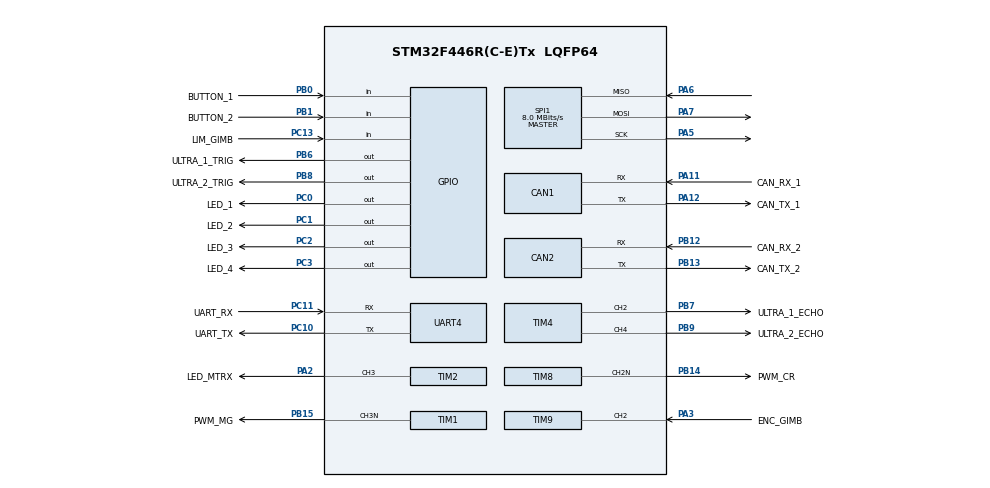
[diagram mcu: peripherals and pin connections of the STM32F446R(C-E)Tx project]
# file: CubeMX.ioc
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CAN1.CalculateTimeQuantum=1000.0
CAN2.CalculateTimeQuantum=1000.0
Mcu.Family=STM32F4
Mcu.Name=STM32F446R(C-E)Tx
Mcu.Package=LQFP64
NVIC.PriorityGroup=NVIC_PRIORITYGROUP_4
PA11.GPIO_Label=CAN_RX_1
PA11.Mode=Master
PA11.Signal=CAN1_RX
PA12.GPIO_Label=CAN_TX_1
PA12.Mode=Master
PA12.Signal=CAN1_TX
PA13.GPIO_Label=SWD_IO
PA13.Mode=Serial_Wire
PA13.Signal=SYS_JTMS-SWDIO
PA14.GPIO_Label=SWD_CLK
PA14.Mode=Serial_Wire
PA14.Signal=SYS_JTCK-SWCLK
PA2.GPIO_Label=LED_MTRX
PA2.Signal=S_TIM2_CH3
PA3.GPIO_Label=ENC_GIMB
PA3.Signal=S_TIM9_CH2
PA5.Mode=Full_Duplex_Master
PA5.Signal=SPI1_SCK
PA6.Mode=Full_Duplex_Master
PA6.Signal=SPI1_MISO
PA7.Mode=Full_Duplex_Master
PA7.Signal=SPI1_MOSI
PB0.GPIO_Label=BUTTON_1
PB0.Signal=GPIO_Input
PB1.GPIO_Label=BUTTON_2
PB1.Signal=GPIO_Input
PB12.GPIO_Label=CAN_RX_2
PB12.Mode=Slave
PB12.Signal=CAN2_RX
PB13.GPIO_Label=CAN_TX_2
PB13.Mode=Slave
PB13.Signal=CAN2_TX
PB14.GPIO_Label=PWM_CR
PB14.Mode=PWM Generation2 CH2N
PB14.Signal=TIM8_CH2N
PB15.GPIO_Label=PWM_MG
PB15.Mode=PWM Generation3 CH3N
PB15.Signal=TIM1_CH3N
PB6.GPIO_Label=ULTRA_1_TRIG
PB6.Signal=GPIO_Output
PB7.GPIO_Label=ULTRA_1_ECHO
PB7.Signal=S_TIM4_CH2
PB8.GPIO_Label=ULTRA_2_TRIG
PB8.Signal=GPIO_Output
PB9.GPIO_Label=ULTRA_2_ECHO
PB9.Signal=S_TIM4_CH4
PC0.GPIO_Label=LED_1
PC0.Signal=GPIO_Output
PC1.GPIO_Label=LED_2
PC1.Signal=GPIO_Output
PC10.GPIO_Label=UART_TX
PC10.Mode=Asynchronous
PC10.Signal=UART4_TX
PC11.GPIO_Label=UART_RX
PC11.Mode=Asynchronous
PC11.Signal=UART4_RX
PC13.GPIO_Label=LIM_GIMB
PC13.Signal=GPIO_Input
PC2.GPIO_Label=LED_3
PC2.Signal=GPIO_Output
PC3.GPIO_Label=LED_4
PC3.Signal=GPIO_Output
PH0-OSC_IN.Mode=HSE-External-Oscillator
PH0-OSC_IN.Signal=RCC_OSC_IN
PH1-OSC_OUT.Mode=HSE-External-Oscillator
PH1-OSC_OUT.Signal=RCC_OSC_OUT
ProjectManager.HeapSize=0x200
ProjectManager.StackSize=0x400
ProjectManager.TargetToolchain=EWARM V8.32
RCC.CortexFreq_Value=16000000
RCC.USBFreq_Value=96000000
RCC.VCOOutputFreq_Value=192000000
SH.S_TIM2_CH3.0=TIM2_CH3,PWM Generation3 CH3
SH.S_TIM4_CH2.0=TIM4_CH2,PWM Generation2 CH2
SH.S_TIM4_CH4.0=TIM4_CH4,PWM Generation4 CH4
SH.S_TIM9_CH2.0=TIM9_CH2,PWM_Input_2
SPI1.CalculateBaudRate=8.0 MBits/s
SPI1.Direction=SPI_DIRECTION_2LINES
SPI1.Mode=SPI_MODE_MASTER
SPI1.VirtualType=VM_MASTER
TIM1.Channel-PWM\ Generation3\ CH3N=TIM_CHANNEL_3
TIM2.Channel-PWM\ Generation3\ CH3=TIM_CHANNEL_3
TIM4.Channel-PWM\ Generation2\ CH2=TIM_CHANNEL_2
TIM4.Channel-PWM\ Generation4\ CH4=TIM_CHANNEL_4
TIM8.Channel-PWM\ Generation2\ CH2N=TIM_CHANNEL_2
UART4.VirtualMode=Asynchronous
VP_TIM12_VS_OPM.Mode=OPM_bit
VP_TIM6_VS_ClockSourceINT.Mode=Enable_Timer
VP_TIM7_VS_ClockSourceINT.Mode=Enable_Timer
board=custom

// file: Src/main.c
/* USER CODE BEGIN Header */
/**
  ******************************************************************************
  * @file           : main.c
  * @brief          : Main program body
  ******************************************************************************
  * @attention
  *
  * <h2><center>&copy; Copyright (c) 2020 STMicroelectronics.
  * All rights reserved.</center></h2>
  *
  * This software component is licensed by ST under BSD 3-Clause license,
  * the "License"; You may not use this file except in compliance with the
  * License. You may obtain a copy of the License at:
  *                        opensource.org/licenses/BSD-3-Clause
  *
  ******************************************************************************
  */
/* USER CODE END Header */

#include "main.h"

CAN_HandleTypeDef hcan1;
CAN_HandleTypeDef hcan2;

SPI_HandleTypeDef hspi1;

TIM_HandleTypeDef htim1;
TIM_HandleTypeDef htim2;
TIM_HandleTypeDef htim4;
TIM_HandleTypeDef htim6;
TIM_HandleTypeDef htim7;
TIM_HandleTypeDef htim8;
TIM_HandleTypeDef htim9;
TIM_HandleTypeDef htim12;

UART_HandleTypeDef huart4;

void SystemClock_Config(void);
static void MX_GPIO_Init(void);
static void MX_CAN1_Init(void);
static void MX_CAN2_Init(void);
static void MX_SPI1_Init(void);
static void MX_TIM1_Init(void);
static void MX_TIM2_Init(void);
static void MX_TIM4_Init(void);
static void MX_TIM6_Init(void);
static void MX_TIM7_Init(void);
static void MX_TIM8_Init(void);
static void MX_TIM9_Init(void);
static void MX_TIM12_Init(void);
static void MX_UART4_Init(void);

int main(void)
{

  /* MCU Configuration--------------------------------------------------------*/

  /* Reset of all peripherals, Initializes the Flash interface and the Systick. */
  HAL_Init();

  /* Configure the system clock */
  SystemClock_Config();

  /* Initialize all configured peripherals */
  MX_GPIO_Init();
  MX_CAN1_Init();
  MX_CAN2_Init();
  MX_SPI1_Init();
  MX_TIM1_Init();
  MX_TIM2_Init();
  MX_TIM4_Init();
  MX_TIM6_Init();
  MX_TIM7_Init();
  MX_TIM8_Init();
  MX_TIM9_Init();
  MX_TIM12_Init();
  MX_UART4_Init();

  /* Infinite loop */
  while (1)
  {

  }
}

void SystemClock_Config(void)
{
  RCC_OscInitTypeDef RCC_OscInitStruct = {0};
  RCC_ClkInitTypeDef RCC_ClkInitStruct = {0};

  /** Configure the main internal regulator output voltage
  */
  __HAL_RCC_PWR_CLK_ENABLE();
  __HAL_PWR_VOLTAGESCALING_CONFIG(PWR_REGULATOR_VOLTAGE_SCALE1);
  /** Initializes the CPU, AHB and APB busses clocks
  */
  RCC_OscInitStruct.OscillatorType = RCC_OSCILLATORTYPE_HSE;
  RCC_OscInitStruct.HSEState = RCC_HSE_ON;
  RCC_OscInitStruct.PLL.PLLState = RCC_PLL_ON;
  RCC_OscInitStruct.PLL.PLLSource = RCC_PLLSOURCE_HSE;
  RCC_OscInitStruct.PLL.PLLM = 25;
  RCC_OscInitStruct.PLL.PLLN = 360;
  RCC_OscInitStruct.PLL.PLLP = RCC_PLLP_DIV2;
  RCC_OscInitStruct.PLL.PLLQ = 2;
  RCC_OscInitStruct.PLL.PLLR = 2;
  if (HAL_RCC_OscConfig(&RCC_OscInitStruct) != HAL_OK)
  {
    Error_Handler();
  }
  /** Activate the Over-Drive mode
  */
  if (HAL_PWREx_EnableOverDrive() != HAL_OK)
  {
    Error_Handler();
  }
  /** Initializes the CPU, AHB and APB busses clocks
  */
  RCC_ClkInitStruct.ClockType = RCC_CLOCKTYPE_HCLK|RCC_CLOCKTYPE_SYSCLK
                              |RCC_CLOCKTYPE_PCLK1|RCC_CLOCKTYPE_PCLK2;
  RCC_ClkInitStruct.SYSCLKSource = RCC_SYSCLKSOURCE_PLLCLK;
  RCC_ClkInitStruct.AHBCLKDivider = RCC_SYSCLK_DIV1;
  RCC_ClkInitStruct.APB1CLKDivider = RCC_HCLK_DIV4;
  RCC_ClkInitStruct.APB2CLKDivider = RCC_HCLK_DIV2;

  if (HAL_RCC_ClockConfig(&RCC_ClkInitStruct, FLASH_LATENCY_5) != HAL_OK)
  {
    Error_Handler();
  }
}

static void MX_CAN1_Init(void)
{

  hcan1.Instance = CAN1;
  hcan1.Init.Prescaler = 16;
  hcan1.Init.Mode = CAN_MODE_NORMAL;
  hcan1.Init.SyncJumpWidth = CAN_SJW_1TQ;
  hcan1.Init.TimeSeg1 = CAN_BS1_1TQ;
  hcan1.Init.TimeSeg2 = CAN_BS2_1TQ;
  hcan1.Init.TimeTriggeredMode = DISABLE;
  hcan1.Init.AutoBusOff = DISABLE;
  hcan1.Init.AutoWakeUp = DISABLE;
  hcan1.Init.AutoRetransmission = DISABLE;
  hcan1.Init.ReceiveFifoLocked = DISABLE;
  hcan1.Init.TransmitFifoPriority = DISABLE;
  if (HAL_CAN_Init(&hcan1) != HAL_OK)
  {
    Error_Handler();
  }

}

static void MX_CAN2_Init(void)
{

  hcan2.Instance = CAN2;
  hcan2.Init.Prescaler = 16;
  hcan2.Init.Mode = CAN_MODE_NORMAL;
  hcan2.Init.SyncJumpWidth = CAN_SJW_1TQ;
  hcan2.Init.TimeSeg1 = CAN_BS1_1TQ;
  hcan2.Init.TimeSeg2 = CAN_BS2_1TQ;
  hcan2.Init.TimeTriggeredMode = DISABLE;
  hcan2.Init.AutoBusOff = DISABLE;
  hcan2.Init.AutoWakeUp = DISABLE;
  hcan2.Init.AutoRetransmission = DISABLE;
  hcan2.Init.ReceiveFifoLocked = DISABLE;
  hcan2.Init.TransmitFifoPriority = DISABLE;
  if (HAL_CAN_Init(&hcan2) != HAL_OK)
  {
    Error_Handler();
  }

}

static void MX_SPI1_Init(void)
{

  /* SPI1 parameter configuration*/
  hspi1.Instance = SPI1;
  hspi1.Init.Mode = SPI_MODE_MASTER;
  hspi1.Init.Direction = SPI_DIRECTION_2LINES;
  hspi1.Init.DataSize = SPI_DATASIZE_8BIT;
  hspi1.Init.CLKPolarity = SPI_POLARITY_LOW;
  hspi1.Init.CLKPhase = SPI_PHASE_1EDGE;
  hspi1.Init.NSS = SPI_NSS_SOFT;
  hspi1.Init.BaudRatePrescaler = SPI_BAUDRATEPRESCALER_2;
  hspi1.Init.FirstBit = SPI_FIRSTBIT_MSB;
  hspi1.Init.TIMode = SPI_TIMODE_DISABLE;
  hspi1.Init.CRCCalculation = SPI_CRCCALCULATION_DISABLE;
  hspi1.Init.CRCPolynomial = 10;
  if (HAL_SPI_Init(&hspi1) != HAL_OK)
  {
    Error_Handler();
  }

}

static void MX_TIM1_Init(void)
{

  TIM_MasterConfigTypeDef sMasterConfig = {0};
  TIM_OC_InitTypeDef sConfigOC = {0};
  TIM_BreakDeadTimeConfigTypeDef sBreakDeadTimeConfig = {0};

  htim1.Instance = TIM1;
  htim1.Init.Prescaler = 0;
  htim1.Init.CounterMode = TIM_COUNTERMODE_UP;
  htim1.Init.Period = 0;
  htim1.Init.ClockDivision = TIM_CLOCKDIVISION_DIV1;
  htim1.Init.RepetitionCounter = 0;
  htim1.Init.AutoReloadPreload = TIM_AUTORELOAD_PRELOAD_DISABLE;
  if (HAL_TIM_PWM_Init(&htim1) != HAL_OK)
  {
    Error_Handler();
  }
  sMasterConfig.MasterOutputTrigger = TIM_TRGO_RESET;
  sMasterConfig.MasterSlaveMode = TIM_MASTERSLAVEMODE_DISABLE;
  if (HAL_TIMEx_MasterConfigSynchronization(&htim1, &sMasterConfig) != HAL_OK)
  {
    Error_Handler();
  }
  sConfigOC.OCMode = TIM_OCMODE_PWM1;
  sConfigOC.Pulse = 0;
  sConfigOC.OCPolarity = TIM_OCPOLARITY_HIGH;
  sConfigOC.OCNPolarity = TIM_OCNPOLARITY_HIGH;
  sConfigOC.OCFastMode = TIM_OCFAST_DISABLE;
  sConfigOC.OCIdleState = TIM_OCIDLESTATE_RESET;
  sConfigOC.OCNIdleState = TIM_OCNIDLESTATE_RESET;
  if (HAL_TIM_PWM_ConfigChannel(&htim1, &sConfigOC, TIM_CHANNEL_3) != HAL_OK)
  {
    Error_Handler();
  }
  sBreakDeadTimeConfig.OffStateRunMode = TIM_OSSR_DISABLE;
  sBreakDeadTimeConfig.OffStateIDLEMode = TIM_OSSI_DISABLE;
  sBreakDeadTimeConfig.LockLevel = TIM_LOCKLEVEL_OFF;
  sBreakDeadTimeConfig.DeadTime = 0;
  sBreakDeadTimeConfig.BreakState = TIM_BREAK_DISABLE;
  sBreakDeadTimeConfig.BreakPolarity = TIM_BREAKPOLARITY_HIGH;
  sBreakDeadTimeConfig.AutomaticOutput = TIM_AUTOMATICOUTPUT_DISABLE;
  if (HAL_TIMEx_ConfigBreakDeadTime(&htim1, &sBreakDeadTimeConfig) != HAL_OK)
  {
    Error_Handler();
  }
  HAL_TIM_MspPostInit(&htim1);

}

static void MX_TIM2_Init(void)
{

  TIM_MasterConfigTypeDef sMasterConfig = {0};
  TIM_OC_InitTypeDef sConfigOC = {0};

  htim2.Instance = TIM2;
  htim2.Init.Prescaler = 0;
  htim2.Init.CounterMode = TIM_COUNTERMODE_UP;
  htim2.Init.Period = 0;
  htim2.Init.ClockDivision = TIM_CLOCKDIVISION_DIV1;
  htim2.Init.AutoReloadPreload = TIM_AUTORELOAD_PRELOAD_DISABLE;
  if (HAL_TIM_PWM_Init(&htim2) != HAL_OK)
  {
    Error_Handler();
  }
  sMasterConfig.MasterOutputTrigger = TIM_TRGO_RESET;
  sMasterConfig.MasterSlaveMode = TIM_MASTERSLAVEMODE_DISABLE;
  if (HAL_TIMEx_MasterConfigSynchronization(&htim2, &sMasterConfig) != HAL_OK)
  {
    Error_Handler();
  }
  sConfigOC.OCMode = TIM_OCMODE_PWM1;
  sConfigOC.Pulse = 0;
  sConfigOC.OCPolarity = TIM_OCPOLARITY_HIGH;
  sConfigOC.OCFastMode = TIM_OCFAST_DISABLE;
  if (HAL_TIM_PWM_ConfigChannel(&htim2, &sConfigOC, TIM_CHANNEL_3) != HAL_OK)
  {
    Error_Handler();
  }
  HAL_TIM_MspPostInit(&htim2);

}

static void MX_TIM4_Init(void)
{

  TIM_MasterConfigTypeDef sMasterConfig = {0};
  TIM_OC_InitTypeDef sConfigOC = {0};

  htim4.Instance = TIM4;
  htim4.Init.Prescaler = 0;
  htim4.Init.CounterMode = TIM_COUNTERMODE_UP;
  htim4.Init.Period = 0;
  htim4.Init.ClockDivision = TIM_CLOCKDIVISION_DIV1;
  htim4.Init.AutoReloadPreload = TIM_AUTORELOAD_PRELOAD_DISABLE;
  if (HAL_TIM_PWM_Init(&htim4) != HAL_OK)
  {
    Error_Handler();
  }
  sMasterConfig.MasterOutputTrigger = TIM_TRGO_RESET;
  sMasterConfig.MasterSlaveMode = TIM_MASTERSLAVEMODE_DISABLE;
  if (HAL_TIMEx_MasterConfigSynchronization(&htim4, &sMasterConfig) != HAL_OK)
  {
    Error_Handler();
  }
  sConfigOC.OCMode = TIM_OCMODE_PWM1;
  sConfigOC.Pulse = 0;
  sConfigOC.OCPolarity = TIM_OCPOLARITY_HIGH;
  sConfigOC.OCFastMode = TIM_OCFAST_DISABLE;
  if (HAL_TIM_PWM_ConfigChannel(&htim4, &sConfigOC, TIM_CHANNEL_2) != HAL_OK)
  {
    Error_Handler();
  }
  if (HAL_TIM_PWM_ConfigChannel(&htim4, &sConfigOC, TIM_CHANNEL_4) != HAL_OK)
  {
    Error_Handler();
  }
  HAL_TIM_MspPostInit(&htim4);

}

static void MX_TIM6_Init(void)
{

  TIM_MasterConfigTypeDef sMasterConfig = {0};

  htim6.Instance = TIM6;
  htim6.Init.Prescaler = 0;
  htim6.Init.CounterMode = TIM_COUNTERMODE_UP;
  htim6.Init.Period = 0;
  htim6.Init.AutoReloadPreload = TIM_AUTORELOAD_PRELOAD_DISABLE;
  if (HAL_TIM_Base_Init(&htim6) != HAL_OK)
  {
    Error_Handler();
  }
  sMasterConfig.MasterOutputTrigger = TIM_TRGO_RESET;
  sMasterConfig.MasterSlaveMode = TIM_MASTERSLAVEMODE_DISABLE;
  if (HAL_TIMEx_MasterConfigSynchronization(&htim6, &sMasterConfig) != HAL_OK)
  {
    Error_Handler();
  }

}

static void MX_TIM7_Init(void)
{

  TIM_MasterConfigTypeDef sMasterConfig = {0};

  htim7.Instance = TIM7;
  htim7.Init.Prescaler = 0;
  htim7.Init.CounterMode = TIM_COUNTERMODE_UP;
  htim7.Init.Period = 0;
  htim7.Init.AutoReloadPreload = TIM_AUTORELOAD_PRELOAD_DISABLE;
  if (HAL_TIM_Base_Init(&htim7) != HAL_OK)
  {
    Error_Handler();
  }
  sMasterConfig.MasterOutputTrigger = TIM_TRGO_RESET;
  sMasterConfig.MasterSlaveMode = TIM_MASTERSLAVEMODE_DISABLE;
  if (HAL_TIMEx_MasterConfigSynchronization(&htim7, &sMasterConfig) != HAL_OK)
  {
    Error_Handler();
  }

}

static void MX_TIM8_Init(void)
{

  TIM_MasterConfigTypeDef sMasterConfig = {0};
  TIM_OC_InitTypeDef sConfigOC = {0};
  TIM_BreakDeadTimeConfigTypeDef sBreakDeadTimeConfig = {0};

  htim8.Instance = TIM8;
  htim8.Init.Prescaler = 0;
  htim8.Init.CounterMode = TIM_COUNTERMODE_UP;
  htim8.Init.Period = 0;
  htim8.Init.ClockDivision = TIM_CLOCKDIVISION_DIV1;
  htim8.Init.RepetitionCounter = 0;
  htim8.Init.AutoReloadPreload = TIM_AUTORELOAD_PRELOAD_DISABLE;
  if (HAL_TIM_PWM_Init(&htim8) != HAL_OK)
  {
    Error_Handler();
  }
  sMasterConfig.MasterOutputTrigger = TIM_TRGO_RESET;
  sMasterConfig.MasterSlaveMode = TIM_MASTERSLAVEMODE_DISABLE;
  if (HAL_TIMEx_MasterConfigSynchronization(&htim8, &sMasterConfig) != HAL_OK)
  {
    Error_Handler();
  }
  sConfigOC.OCMode = TIM_OCMODE_PWM1;
  sConfigOC.Pulse = 0;
  sConfigOC.OCPolarity = TIM_OCPOLARITY_HIGH;
  sConfigOC.OCNPolarity = TIM_OCNPOLARITY_HIGH;
  sConfigOC.OCFastMode = TIM_OCFAST_DISABLE;
  sConfigOC.OCIdleState = TIM_OCIDLESTATE_RESET;
  sConfigOC.OCNIdleState = TIM_OCNIDLESTATE_RESET;
  if (HAL_TIM_PWM_ConfigChannel(&htim8, &sConfigOC, TIM_CHANNEL_2) != HAL_OK)
  {
    Error_Handler();
  }
  sBreakDeadTimeConfig.OffStateRunMode = TIM_OSSR_DISABLE;
  sBreakDeadTimeConfig.OffStateIDLEMode = TIM_OSSI_DISABLE;
  sBreakDeadTimeConfig.LockLevel = TIM_LOCKLEVEL_OFF;
  sBreakDeadTimeConfig.DeadTime = 0;
  sBreakDeadTimeConfig.BreakState = TIM_BREAK_DISABLE;
  sBreakDeadTimeConfig.BreakPolarity = TIM_BREAKPOLARITY_HIGH;
  sBreakDeadTimeConfig.AutomaticOutput = TIM_AUTOMATICOUTPUT_DISABLE;
  if (HAL_TIMEx_ConfigBreakDeadTime(&htim8, &sBreakDeadTimeConfig) != HAL_OK)
  {
    Error_Handler();
  }
  HAL_TIM_MspPostInit(&htim8);

}

static void MX_TIM9_Init(void)
{

  TIM_SlaveConfigTypeDef sSlaveConfig = {0};
  TIM_IC_InitTypeDef sConfigIC = {0};

  htim9.Instance = TIM9;
  htim9.Init.Prescaler = 0;
  htim9.Init.CounterMode = TIM_COUNTERMODE_UP;
  htim9.Init.Period = 0;
  htim9.Init.ClockDivision = TIM_CLOCKDIVISION_DIV1;
  htim9.Init.AutoReloadPreload = TIM_AUTORELOAD_PRELOAD_DISABLE;
  if (HAL_TIM_IC_Init(&htim9) != HAL_OK)
  {
    Error_Handler();
  }
  sSlaveConfig.SlaveMode = TIM_SLAVEMODE_RESET;
  sSlaveConfig.InputTrigger = TIM_TS_TI2FP2;
  sSlaveConfig.TriggerPolarity = TIM_INPUTCHANNELPOLARITY_FALLING;
  sSlaveConfig.TriggerPrescaler = TIM_ICPSC_DIV1;
  sSlaveConfig.TriggerFilter = 0;
  if (HAL_TIM_SlaveConfigSynchro(&htim9, &sSlaveConfig) != HAL_OK)
  {
    Error_Handler();
  }
  sConfigIC.ICPolarity = TIM_INPUTCHANNELPOLARITY_RISING;
  sConfigIC.ICSelection = TIM_ICSELECTION_INDIRECTTI;
  sConfigIC.ICPrescaler = TIM_ICPSC_DIV1;
  sConfigIC.ICFilter = 0;
  if (HAL_TIM_IC_ConfigChannel(&htim9, &sConfigIC, TIM_CHANNEL_1) != HAL_OK)
  {
    Error_Handler();
  }
  sConfigIC.ICPolarity = TIM_INPUTCHANNELPOLARITY_FALLING;
  sConfigIC.ICSelection = TIM_ICSELECTION_DIRECTTI;
  if (HAL_TIM_IC_ConfigChannel(&htim9, &sConfigIC, TIM_CHANNEL_2) != HAL_OK)
  {
    Error_Handler();
  }

}

static void MX_TIM12_Init(void)
{

  htim12.Instance = TIM12;
  htim12.Init.Prescaler = 0;
  htim12.Init.CounterMode = TIM_COUNTERMODE_UP;
  htim12.Init.Period = 0;
  htim12.Init.ClockDivision = TIM_CLOCKDIVISION_DIV1;
  htim12.Init.AutoReloadPreload = TIM_AUTORELOAD_PRELOAD_DISABLE;
  if (HAL_TIM_OnePulse_Init(&htim12, TIM_OPMODE_SINGLE) != HAL_OK)
  {
    Error_Handler();
  }

}

static void MX_UART4_Init(void)
{

  huart4.Instance = UART4;
  huart4.Init.BaudRate = 115200;
  huart4.Init.WordLength = UART_WORDLENGTH_8B;
  huart4.Init.StopBits = UART_STOPBITS_1;
  huart4.Init.Parity = UART_PARITY_NONE;
  huart4.Init.Mode = UART_MODE_TX_RX;
  huart4.Init.HwFlowCtl = UART_HWCONTROL_NONE;
  huart4.Init.OverSampling = UART_OVERSAMPLING_16;
  if (HAL_UART_Init(&huart4) != HAL_OK)
  {
    Error_Handler();
  }

}

static void MX_GPIO_Init(void)
{
  GPIO_InitTypeDef GPIO_InitStruct = {0};

  /* GPIO Ports Clock Enable */
  __HAL_RCC_GPIOC_CLK_ENABLE();
  __HAL_RCC_GPIOH_CLK_ENABLE();
  __HAL_RCC_GPIOA_CLK_ENABLE();
  __HAL_RCC_GPIOB_CLK_ENABLE();

  /*Configure GPIO pin Output Level */
  HAL_GPIO_WritePin(GPIOC, LED_1_Pin|LED_2_Pin|LED_3_Pin|LED_4_Pin, GPIO_PIN_RESET);

  /*Configure GPIO pin Output Level */
  HAL_GPIO_WritePin(GPIOB, ULTRA_1_TRIG_Pin|ULTRA_2_TRIG_Pin, GPIO_PIN_RESET);

  /*Configure GPIO pin : LIM_GIMB_Pin */
  GPIO_InitStruct.Pin = LIM_GIMB_Pin;
  GPIO_InitStruct.Mode = GPIO_MODE_INPUT;
  GPIO_InitStruct.Pull = GPIO_NOPULL;
  HAL_GPIO_Init(LIM_GIMB_GPIO_Port, &GPIO_InitStruct);

  /*Configure GPIO pins : LED_1_Pin LED_2_Pin LED_3_Pin LED_4_Pin */
  GPIO_InitStruct.Pin = LED_1_Pin|LED_2_Pin|LED_3_Pin|LED_4_Pin;
  GPIO_InitStruct.Mode = GPIO_MODE_OUTPUT_PP;
  GPIO_InitStruct.Pull = GPIO_NOPULL;
  GPIO_InitStruct.Speed = GPIO_SPEED_FREQ_LOW;
  HAL_GPIO_Init(GPIOC, &GPIO_InitStruct);

  /*Configure GPIO pins : BUTTON_1_Pin BUTTON_2_Pin */
  GPIO_InitStruct.Pin = BUTTON_1_Pin|BUTTON_2_Pin;
  GPIO_InitStruct.Mode = GPIO_MODE_INPUT;
  GPIO_InitStruct.Pull = GPIO_NOPULL;
  HAL_GPIO_Init(GPIOB, &GPIO_InitStruct);

  /*Configure GPIO pins : ULTRA_1_TRIG_Pin ULTRA_2_TRIG_Pin */
  GPIO_InitStruct.Pin = ULTRA_1_TRIG_Pin|ULTRA_2_TRIG_Pin;
  GPIO_InitStruct.Mode = GPIO_MODE_OUTPUT_PP;
  GPIO_InitStruct.Pull = GPIO_NOPULL;
  GPIO_InitStruct.Speed = GPIO_SPEED_FREQ_LOW;
  HAL_GPIO_Init(GPIOB, &GPIO_InitStruct);

}

void Error_Handler(void)
{
}

/************************ (C) COPYRIGHT STMicroelectronics *****END OF FILE****/
